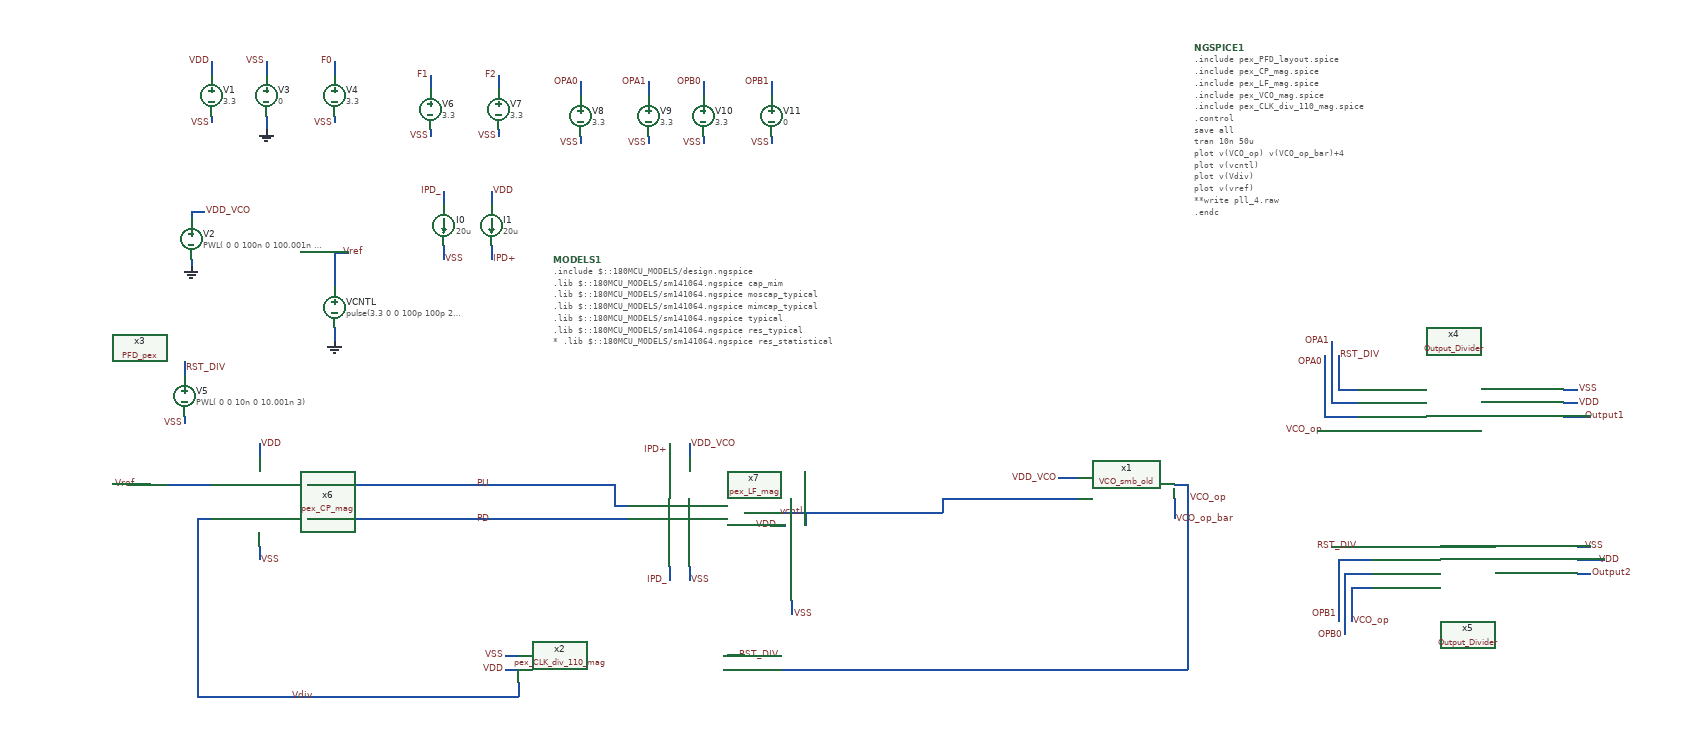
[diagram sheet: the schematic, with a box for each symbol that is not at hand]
v {xschem version=3.1.0 file_version=1.2
}
G {}
K {}
V {}
S {}
E {}
N 330 -520 330 -500 {
lab=VDD}
N 330 -370 330 -350 {
lab=VSS}
N 240 -460 260 -460 {
lab=Vref}
N 240 -410 260 -410 {
lab=Vdiv}
N 400 -410 420 -410 {
lab=PD}
N 160 -460 220 -460 {
lab=Vref}
N 220 -460 240 -460 {
lab=Vref}
N 420 -460 510 -460 {
lab=PU}
N 420 -410 510 -410 {
lab=PD}
N 700 -460 850 -460 {
lab=PU}
N 700 -410 850 -410 {
lab=PD}
N 240 -410 240 -280 {
lab=Vdiv}
N 240 -180 240 -150 {
lab=Vdiv}
N 250 -150 540 -150 {
lab=Vdiv}
N 240 -280 240 -180 {
lab=Vdiv}
N 240 -150 250 -150 {
lab=Vdiv}
N 400 -460 420 -460 {
lab=PU}
N 510 -460 700 -460 {
lab=PU}
N 510 -410 700 -410 {
lab=PD}
N 440 -690 440 -670 {
lab=GND}
N 230 -790 230 -780 {
lab=GND}
N 440 -800 460 -800 {
lab=Vref}
N 260 -1000 260 -990 {
lab=VSS}
N 260 -1080 260 -1060 {
lab=VDD}
N 340 -1080 340 -1060 {
lab=VSS}
N 340 -1000 340 -980 {
lab=GND}
N 540 -150 710 -150 {
lab=Vdiv}
N 1040 -190 1690 -190 {
lab=VCO_op}
N 220 -560 220 -550 {
lab=VSS}
N 220 -640 220 -620 {
lab=RST_DIV}
N 1690 -440 1690 -420 {
lab=VCO_op}
N 1200 -420 1210 -420 {
lab=vcntl}
N 440 -800 440 -750 {
lab=Vref}
N 1010 -190 1030 -190 {
lab=VCO_op}
N 1030 -190 1040 -190 {
lab=VCO_op}
N 1690 -420 1690 -190 {
lab=VCO_op}
N 230 -860 230 -850 {
lab=VDD_VCO}
N 230 -860 250 -860 {
lab=VDD_VCO}
N 580 -980 580 -970 {
lab=VSS}
N 580 -1060 580 -1040 {
lab=F1}
N 440 -1000 440 -990 {
lab=VSS}
N 440 -1080 440 -1060 {
lab=F0}
N 680 -980 680 -970 {
lab=VSS}
N 680 -1060 680 -1040 {
lab=F2}
N 1910 -600 1940 -600 {
lab=RST_DIV}
N 1910 -650 1910 -600 {
lab=RST_DIV}
N 1880 -540 1940 -540 {
lab=VCO_op_bar}
N 1900 -580 1940 -580 {
lab=OPA1}
N 1900 -650 1900 -580 {
lab=OPA1}
N 1890 -560 1940 -560 {
lab=OPA0}
N 1890 -650 1890 -560 {
lab=OPA0}
N 2240 -600 2260 -600 {
lab=VSS}
N 2240 -580 2260 -580 {
lab=VDD}
N 2240 -560 2280 -560 {
lab=Output1}
N 1900 -670 1900 -650 {
lab=OPA1}
N 1930 -310 1960 -310 {
lab=VCO_op}
N 1930 -310 1930 -260 {
lab=VCO_op}
N 1900 -370 1960 -370 {
lab=RST_DIV}
N 1920 -330 1960 -330 {
lab=OPB0}
N 1920 -330 1920 -260 {
lab=OPB0}
N 1910 -350 1960 -350 {
lab=OPB1}
N 1910 -350 1910 -260 {
lab=OPB1}
N 2260 -370 2280 -370 {
lab=VSS}
N 2260 -330 2280 -330 {
lab=Output2}
N 2260 -350 2300 -350 {
lab=VDD}
N 1920 -260 1920 -240 {
lab=OPB0}
N 800 -970 800 -960 {
lab=VSS}
N 800 -1050 800 -1030 {
lab=OPA0}
N 900 -970 900 -960 {
lab=VSS}
N 900 -1050 900 -1030 {
lab=OPA1}
N 980 -970 980 -960 {
lab=VSS}
N 980 -1050 980 -1030 {
lab=OPB0}
N 1080 -970 1080 -960 {
lab=VSS}
N 1080 -1050 1080 -1030 {
lab=OPB1}
N 960 -520 960 -500 {
lab=VDD_VCO}
N 960 -340 960 -320 {
lab=VSS}
N 850 -460 850 -440 {
lab=PU}
N 850 -440 850 -430 {
lab=PU}
N 850 -430 870 -430 {
lab=PU}
N 850 -410 870 -410 {
lab=PD}
N 1110 -290 1110 -270 {
lab=VSS}
N 930 -520 930 -500 {
lab=IPD+}
N 930 -340 930 -320 {
lab=IPD_}
N 1040 -420 1200 -420 {
lab=vcntl}
N 600 -810 600 -790 {
lab=VSS}
N 670 -810 670 -790 {
lab=IPD+}
N 600 -890 600 -870 {
lab=IPD_}
N 670 -890 670 -870 {
lab=VDD}
N 140 -460 170 -460 {
lab=Vref}
N 1130 -420 1130 -400 {
lab=vcntl}
N 1080 -400 1100 -400 {
lab=VDD}
N 1330 -440 1370 -440 {
lab=vcntl}
N 1690 -460 1690 -440 {
lab=VCO_op}
N 1670 -460 1690 -460 {
lab=VCO_op}
N 1670 -440 1670 -410 {
lab=VCO_op_bar}
N 1330 -440 1330 -420 {
lab=vcntl}
N 1210 -420 1330 -420 {
lab=vcntl}
N 710 -170 710 -150 {
lab=Vdiv}
N 700 -190 710 -190 {
lab=VDD}
N 690 -190 700 -190 {
lab=VDD}
N 690 -210 710 -210 {
lab=VSS}
N 1010 -210 1040 -210 {
lab=RST_DIV}
N 1500 -470 1530 -470 {
lab=VDD_VCO}
N 1370 -440 1530 -440 {
lab=vcntl}
C {devices/lab_pin.sym} 330 -520 2 0 {name=p9 sig_type=std_logic lab=VDD}
C {devices/lab_wire.sym} 330 -350 2 0 {name=p10 sig_type=std_logic lab=VSS}
C {devices/lab_pin.sym} 410 -150 3 0 {name=p28 sig_type=std_logic lab=Vdiv
}
C {devices/lab_pin.sym} 1690 -440 2 0 {name=p36 sig_type=std_logic lab=VCO_op
}
C {devices/vsource.sym} 440 -720 0 0 {name=VCNTL value="pulse(3.3 0 0 100p 100p 250n 500n)"}
C {devices/gnd.sym} 440 -670 0 0 {name=l2 lab=GND}
C {devices/gnd.sym} 230 -780 0 0 {name=l1 lab=GND}
C {devices/vsource.sym} 230 -820 0 0 {name=V2 value=" PWL( 0 0 100n 0 100.001n 3.3)"}
C {devices/code_shown.sym} 1700 -1100 0 1 {name=NGSPICE1 only_toplevel=true
value="
.include "pex_PFD_layout.spice"
.include "pex_CP_mag.spice"
.include "pex_LF_mag.spice"
.include "pex_VCO_mag.spice"
.include "pex_CLK_div_110_mag.spice"
.control
save all
tran 10n 50u 
plot v(VCO_op) v(VCO_op_bar)+4
plot v(vcntl)
plot v(Vdiv)
plot v(vref)
**write pll_4.raw
.endc
"}
C {devices/vsource.sym} 260 -1030 0 0 {name=V1 value=3.3}
C {devices/vsource.sym} 340 -1030 0 0 {name=V3 value=0}
C {devices/lab_wire.sym} 340 -1080 0 0 {name=p1 sig_type=std_logic lab=VSS}
C {devices/lab_wire.sym} 260 -990 0 0 {name=p3 sig_type=std_logic lab=VSS
}
C {devices/lab_wire.sym} 260 -1080 0 0 {name=p4 sig_type=std_logic lab=VDD}
C {devices/gnd.sym} 340 -980 0 0 {name=l3 lab=GND}
C {devices/lab_pin.sym} 1670 -410 2 0 {name=p5 sig_type=std_logic lab=VCO_op_bar
}
C {devices/lab_pin.sym} 250 -860 2 0 {name=p11 sig_type=std_logic lab=VDD_VCO}
C {devices/lab_pin.sym} 450 -800 2 0 {name=p12 sig_type=std_logic lab=Vref
}
C {devices/lab_wire.sym} 220 -550 0 0 {name=p13 sig_type=std_logic lab=VSS
}
C {devices/vsource.sym} 220 -590 0 0 {name=V5 value=" PWL( 0 0 10n 0 10.001n 3)"}
C {devices/lab_pin.sym} 1130 -420 1 0 {name=p14 sig_type=std_logic lab=vcntl
}
C {devices/lab_pin.sym} 670 -460 1 0 {name=p18 sig_type=std_logic lab=PU}
C {devices/lab_pin.sym} 670 -410 1 0 {name=p19 sig_type=std_logic lab=PD}
C {devices/vsource.sym} 580 -1010 0 0 {name=V6 value=3.3}
C {devices/lab_wire.sym} 580 -970 0 0 {name=p26 sig_type=std_logic lab=VSS
}
C {devices/lab_wire.sym} 580 -1060 0 0 {name=p27 sig_type=std_logic lab=F1}
C {devices/vsource.sym} 440 -1030 0 0 {name=V4 value=3.3}
C {devices/lab_wire.sym} 440 -990 0 0 {name=p23 sig_type=std_logic lab=VSS
}
C {devices/lab_wire.sym} 440 -1080 0 0 {name=p25 sig_type=std_logic lab=F0}
C {devices/vsource.sym} 680 -1010 0 0 {name=V7 value=3.3}
C {devices/lab_wire.sym} 680 -970 0 0 {name=p29 sig_type=std_logic lab=VSS
}
C {devices/lab_wire.sym} 680 -1060 0 0 {name=p30 sig_type=std_logic lab=F2}
C {devices/lab_pin.sym} 2260 -580 2 0 {name=p31 sig_type=std_logic lab=VDD}
C {devices/lab_pin.sym} 2260 -600 2 0 {name=p32 sig_type=std_logic lab=VSS}
C {devices/lab_wire.sym} 1890 -640 0 0 {name=p82 sig_type=std_logic lab=OPA0}
C {devices/lab_wire.sym} 1900 -670 0 0 {name=p83 sig_type=std_logic lab=OPA1}
C {devices/lab_pin.sym} 1910 -650 2 0 {name=p33 sig_type=std_logic lab=RST_DIV}
C {devices/lab_pin.sym} 2270 -560 2 0 {name=p84 sig_type=std_logic lab=Output1}
C {devices/lab_pin.sym} 2290 -350 0 1 {name=p85 sig_type=std_logic lab=VDD}
C {devices/lab_pin.sym} 2270 -370 0 1 {name=p86 sig_type=std_logic lab=VSS}
C {devices/lab_wire.sym} 1910 -270 2 1 {name=p87 sig_type=std_logic lab=OPB1}
C {devices/lab_wire.sym} 1920 -240 2 1 {name=p88 sig_type=std_logic lab=OPB0}
C {devices/lab_pin.sym} 2280 -330 0 1 {name=p90 sig_type=std_logic lab=Output2}
C {Output_Divider.sym} 2110 -340 0 0 {name=x5}
C {devices/lab_pin.sym} 1940 -370 1 0 {name=p34 sig_type=std_logic lab=RST_DIV}
C {devices/lab_pin.sym} 1930 -260 2 0 {name=p35 sig_type=std_logic lab=VCO_op
}
C {devices/lab_pin.sym} 1890 -540 2 1 {name=p40 sig_type=std_logic lab=VCO_op
}
C {devices/vsource.sym} 800 -1000 0 0 {name=V8 value=3.3}
C {devices/lab_wire.sym} 800 -960 0 0 {name=p41 sig_type=std_logic lab=VSS
}
C {devices/lab_wire.sym} 800 -1050 0 0 {name=p42 sig_type=std_logic lab=OPA0}
C {devices/vsource.sym} 900 -1000 0 0 {name=V9 value=3.3}
C {devices/lab_wire.sym} 900 -960 0 0 {name=p43 sig_type=std_logic lab=VSS
}
C {devices/lab_wire.sym} 900 -1050 0 0 {name=p44 sig_type=std_logic lab=OPA1}
C {devices/vsource.sym} 980 -1000 0 0 {name=V10 value=3.3}
C {devices/lab_wire.sym} 980 -960 0 0 {name=p45 sig_type=std_logic lab=VSS
}
C {devices/lab_wire.sym} 980 -1050 0 0 {name=p46 sig_type=std_logic lab=OPB0
}
C {devices/vsource.sym} 1080 -1000 0 0 {name=V11 value=0}
C {devices/lab_wire.sym} 1080 -960 0 0 {name=p47 sig_type=std_logic lab=VSS
}
C {devices/lab_wire.sym} 1080 -1050 0 0 {name=p48 sig_type=std_logic lab=OPB1}
C {devices/lab_pin.sym} 220 -630 2 0 {name=p38 sig_type=std_logic lab=RST_DIV}
C {devices/lab_wire.sym} 960 -320 2 0 {name=p8 sig_type=std_logic lab=VSS}
C {devices/lab_wire.sym} 1110 -270 2 0 {name=p15 sig_type=std_logic lab=VSS}
C {devices/lab_wire.sym} 930 -510 0 0 {name=p16 sig_type=std_logic lab=IPD+}
C {devices/lab_wire.sym} 930 -320 0 0 {name=p49 sig_type=std_logic lab=IPD_}
C {devices/isource.sym} 600 -840 0 0 {name=I0 value=20u}
C {devices/isource.sym} 670 -840 0 0 {name=I1 value=20u}
C {devices/lab_wire.sym} 600 -890 0 0 {name=p50 sig_type=std_logic lab=IPD_}
C {devices/lab_wire.sym} 670 -790 2 0 {name=p51 sig_type=std_logic lab=IPD+}
C {devices/lab_wire.sym} 600 -790 2 0 {name=p52 sig_type=std_logic lab=VSS}
C {devices/lab_wire.sym} 670 -890 2 0 {name=p53 sig_type=std_logic lab=VDD}
C {devices/lab_pin.sym} 150 -460 0 0 {name=p54 sig_type=std_logic lab=Vref
}
C {Output_Divider.sym} 2090 -570 0 0 {name=x4}
C {devices/code_shown.sym} 760 -790 0 0 {name=MODELS1 only_toplevel=true
format="tcleval( @value )"
value="
.include $::180MCU_MODELS/design.ngspice
.lib $::180MCU_MODELS/sm141064.ngspice cap_mim
.lib $::180MCU_MODELS/sm141064.ngspice moscap_typical
.lib $::180MCU_MODELS/sm141064.ngspice mimcap_typical
.lib $::180MCU_MODELS/sm141064.ngspice typical
.lib $::180MCU_MODELS/sm141064.ngspice res_typical
* .lib $::180MCU_MODELS/sm141064.ngspice res_statistical
"}
C {devices/lab_pin.sym} 1090 -400 0 0 {name=p24 sig_type=std_logic lab=VDD}
C {PFD_pex.sym} 40 -250 0 0 {name=x3}
C {devices/lab_wire.sym} 690 -210 0 0 {name=p6 sig_type=std_logic lab=VSS}
C {devices/lab_pin.sym} 690 -190 0 0 {name=p7 sig_type=std_logic lab=VDD}
C {devices/lab_pin.sym} 1030 -210 2 0 {name=p17 sig_type=std_logic lab=RST_DIV}
C {pex_CLK_div_110_mag.sym} 860 -190 0 1 {name=x2}
C {pex_LF_mag.sym} 970 -240 0 0 {name=x7}
C {pex_CP_mag.sym} 380 -220 0 0 {name=x6}
C {devices/lab_pin.sym} 960 -520 2 0 {name=p20 sig_type=std_logic lab=VDD_VCO}
C {VCO_smb_old.sym} 1680 -450 0 0 {name=x1}
C {devices/lab_pin.sym} 1500 -470 0 0 {name=p21 sig_type=std_logic lab=VDD_VCO}
